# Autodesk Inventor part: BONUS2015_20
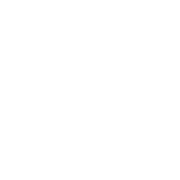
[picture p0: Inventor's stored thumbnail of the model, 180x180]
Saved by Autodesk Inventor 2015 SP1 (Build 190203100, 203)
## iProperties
Created: 2015-05
Part Number: BONUS2015_20
Material: Generisch
Document SubType Name: Modeling
Density: 1 g/cm^3
Appearance: Vorgabe
xx: 20
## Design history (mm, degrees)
